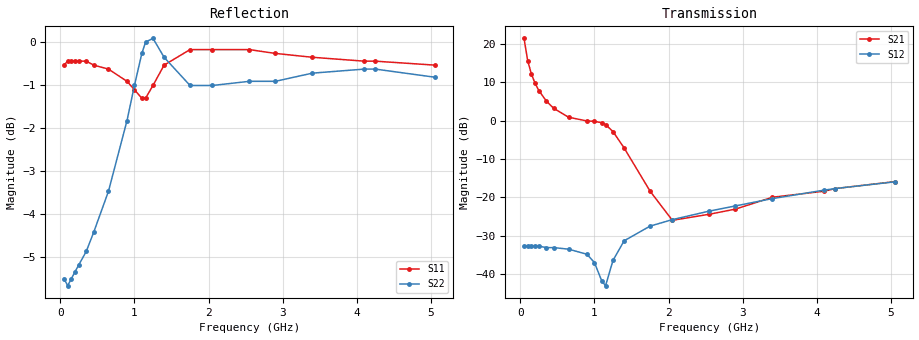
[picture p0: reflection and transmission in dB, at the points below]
!AT-36408
!S-PARAMETERS at Vce=6.0 V  Ic=50 mA.  LAST UPDATED 08-05-96
# ghz s ma r 50
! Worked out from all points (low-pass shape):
!   101 points, 50 MHz to 5.05 GHz, reference 50 ohm
!   highest |S21| = 21.50 dB at 50 MHz (marker M1); lowest = -26.0 dB at 2.05 GHz (marker M2)
!   |S21| within 3 dB of the highest: start of sweep to 75.47 MHz
!   lowest |S11| = -1.3 dB at 1.1 GHz (marker M3), VSWR 13.29, Z = 3.79 + j3.91 ohm
!   |S11| at or under -10 dB: nowhere
!   |S22| runs from -5.7 to 0.1 dB; largest |S21 - S12| = 12
!   S11 on the Smith chart (normalised r, x): 50 MHz: 0.03, -0.10; 650 MHz: 0.04, +0.06; 2.9 GHz: 0.02, +0.28; 4.1 GHz: 0.03, +0.46; 5.05 GHz: 0.04, +0.66
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0.05  0.94 -169.0  11.88 94.0  0.023 8.0  0.53 -156.0
0.1  0.95 -175.0  6.03 86.0  0.023 5.0  0.52 -165.0
0.15  0.95 -178.0  4.05 81.0  0.023 4.0  0.53 -167.0
0.2  0.95 -180.0  3.06 77.0  0.023 3.0  0.54 -166.0
0.25  0.95 179.0  2.47 73.0  0.023 3.0  0.55 -165.0
0.35  0.95 177.0  1.81 65.0  0.022 3.0  0.57 -163.0
0.45  0.94 176.0  1.45 57.0  0.022 2.0  0.6 -161.0
0.65  0.93 173.0  1.11 40.0  0.021 0.0  0.67 -158.0
0.9  0.9 170.0  0.99 12.0  0.018 -15.0  0.81 -156.0
1  0.88 170.0  0.98 -4.0  0.014 -34.0  0.89 -157.0
1.1  0.86 171.0  0.94 -25.0  0.008 -80.0  0.97 -160.0
1.15  0.86 172.0  0.89 -37.0  0.007 -127.0  1 -163.0
1.25  0.89 173.0  0.72 -62.0  0.015 162.0  1.01 -169.0
1.4  0.94 171.0  0.44 -93.0  0.027 122.0  0.96 -174.0
1.75  0.98 165.0  0.12 -140.0  0.042 94.0  0.89 -175.0
2.05  0.98 161.0  0.05 169.0  0.051 86.0  0.89 -175.0
2.55  0.98 154.0  0.06 100.0  0.066 79.0  0.9 -176.0
2.9  0.97 149.0  0.07 85.0  0.077 76.0  0.9 -177.0
3.4  0.96 142.0  0.1 73.0  0.096 72.0  0.92 -178.0
4.1  0.95 131.0  0.12 62.0  0.124 62.0  0.93 177.0
4.25  0.95 129.0  0.13 60.0  0.13 59.0  0.93 176.0
5.05  0.94 113.0  0.16 49.0  0.159 49.0  0.91 169.0
